VERSION 5.8 ;
BUSBITCHARS "[]" ;
DIVIDERCHAR "/" ;
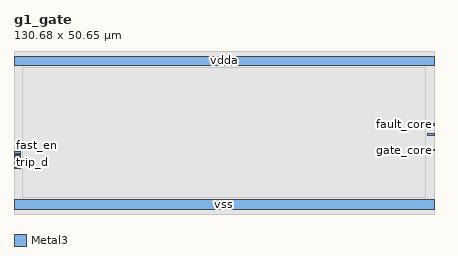
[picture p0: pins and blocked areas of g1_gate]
MACRO g1_gate
  CLASS BLOCK ;
  ORIGIN 0 0 ;
  FOREIGN g1_gate 0 0 ;
  SIZE 130.680 BY 50.650 ;
  SYMMETRY X Y ;
  PIN trip_d
    DIRECTION INOUT ;
    USE SIGNAL ;
    PORT
      LAYER Metal3 ;
        RECT 0.000 15.650 2.000 16.150 ;
    END
  END trip_d
  PIN clr_d
    DIRECTION INOUT ;
    USE SIGNAL ;
    PORT
      LAYER Metal3 ;
        RECT 0.000 16.450 2.000 16.950 ;
    END
  END clr_d
  PIN fast_en
    DIRECTION INOUT ;
    USE SIGNAL ;
    PORT
      LAYER Metal3 ;
        RECT 0.000 18.850 2.000 19.350 ;
    END
  END fast_en
  PIN hard_cmp
    DIRECTION INOUT ;
    USE SIGNAL ;
    PORT
      LAYER Metal3 ;
        RECT 0.000 18.050 2.000 18.550 ;
    END
  END hard_cmp
  PIN en_core
    DIRECTION INOUT ;
    USE SIGNAL ;
    PORT
      LAYER Metal3 ;
        RECT 0.000 17.250 2.000 17.750 ;
    END
  END en_core
  PIN gate_core
    DIRECTION INOUT ;
    USE SIGNAL ;
    PORT
      LAYER Metal3 ;
        RECT 128.680 19.650 130.680 20.150 ;
    END
  END gate_core
  PIN fault_core
    DIRECTION INOUT ;
    USE SIGNAL ;
    PORT
      LAYER Metal3 ;
        RECT 128.680 27.650 130.680 28.150 ;
    END
  END fault_core
  PIN tripped
    DIRECTION INOUT ;
    USE SIGNAL ;
    PORT
      LAYER Metal3 ;
        RECT 128.680 24.450 130.680 24.950 ;
    END
  END tripped
  PIN vss
    DIRECTION INOUT ;
    USE GROUND ;
    PORT
      LAYER Metal3 ;
        RECT 0.000 1.500 130.680 4.500 ;
    END
  END vss
  PIN vdda
    DIRECTION INOUT ;
    USE POWER ;
    PORT
      LAYER Metal3 ;
        RECT 0.000 46.150 130.680 49.150 ;
    END
  END vdda
  PIN vdd
    DIRECTION INOUT ;
    USE POWER ;
    PORT
      LAYER Metal3 ;
        RECT 0.000 14.080 2.000 14.580 ;
    END
  END vdd
  OBS
    LAYER Metal1 ;
      RECT 0.000 0.000 130.680 50.650 ;
    LAYER Metal2 ;
      RECT 0.000 0.000 130.680 50.650 ;
    LAYER Metal3 ;
      RECT 2.500 5.000 128.180 45.650 ;
  END
END g1_gate
END LIBRARY
